# Generated by OpenFakeRAM
VERSION 5.7 ;
BUSBITCHARS "[]" ;
PROPERTYDEFINITIONS
  MACRO width INTEGER ;
  MACRO depth INTEGER ;
  MACRO banks INTEGER ;
END PROPERTYDEFINITIONS
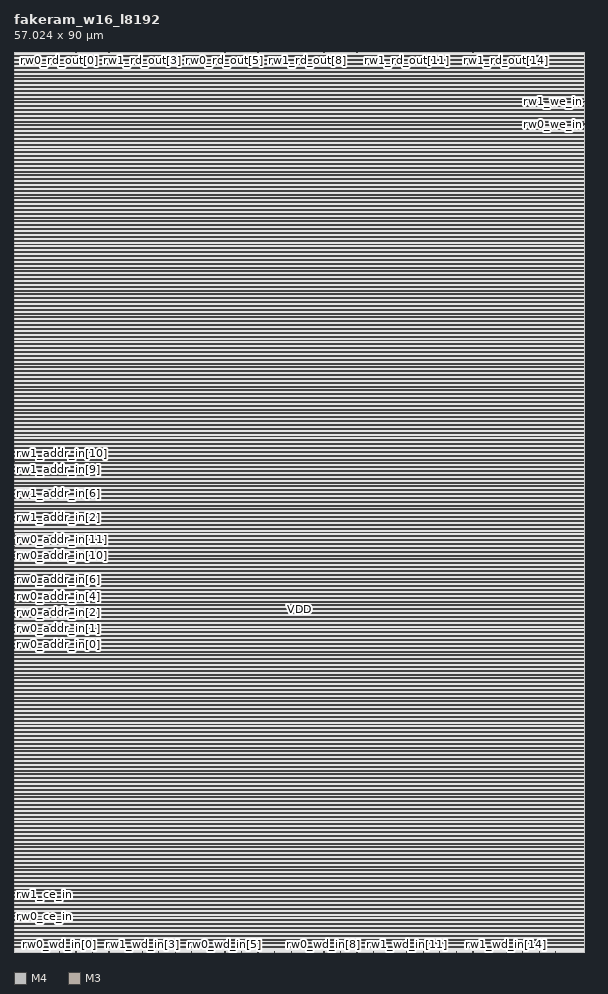
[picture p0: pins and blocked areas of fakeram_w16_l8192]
MACRO fakeram_w16_l8192
  PROPERTY width 16 ;
  PROPERTY depth 4096 ;
  PROPERTY banks 1 ;
  FOREIGN fakeram_w16_l8192 0 0 ;
  SYMMETRY X Y R90 ;
  SIZE 57.024 BY 90.000 ;
  CLASS BLOCK ;
  PIN rw0_clk
    DIRECTION INPUT ;
    USE SIGNAL ;
    SHAPE ABUTMENT ;
    PORT
      LAYER M4 ;
      RECT 0.000 2.724 0.048 2.748 ;
    END
  END rw0_clk
  PIN rw0_ce_in
    DIRECTION INPUT ;
    USE SIGNAL ;
    SHAPE ABUTMENT ;
    PORT
      LAYER M4 ;
      RECT 0.000 3.588 0.048 3.612 ;
    END
  END rw0_ce_in
  PIN rw1_clk
    DIRECTION INPUT ;
    USE SIGNAL ;
    SHAPE ABUTMENT ;
    PORT
      LAYER M4 ;
      RECT 0.000 4.068 0.048 4.092 ;
    END
  END rw1_clk
  PIN rw1_ce_in
    DIRECTION INPUT ;
    USE SIGNAL ;
    SHAPE ABUTMENT ;
    PORT
      LAYER M4 ;
      RECT 0.000 4.932 0.048 4.956 ;
    END
  END rw1_ce_in
  PIN rw0_addr_in[0]
    DIRECTION INPUT ;
    USE SIGNAL ;
    SHAPE ABUTMENT ;
    PORT
      LAYER M4 ;
      RECT 0.000 31.524 0.048 31.548 ;
    END
  END rw0_addr_in[0]
  PIN rw0_addr_in[1]
    DIRECTION INPUT ;
    USE SIGNAL ;
    SHAPE ABUTMENT ;
    PORT
      LAYER M4 ;
      RECT 0.000 32.340 0.048 32.364 ;
    END
  END rw0_addr_in[1]
  PIN rw0_addr_in[2]
    DIRECTION INPUT ;
    USE SIGNAL ;
    SHAPE ABUTMENT ;
    PORT
      LAYER M4 ;
      RECT 0.000 33.156 0.048 33.180 ;
    END
  END rw0_addr_in[2]
  PIN rw0_addr_in[3]
    DIRECTION INPUT ;
    USE SIGNAL ;
    SHAPE ABUTMENT ;
    PORT
      LAYER M4 ;
      RECT 0.000 33.972 0.048 33.996 ;
    END
  END rw0_addr_in[3]
  PIN rw0_addr_in[4]
    DIRECTION INPUT ;
    USE SIGNAL ;
    SHAPE ABUTMENT ;
    PORT
      LAYER M4 ;
      RECT 0.000 34.788 0.048 34.812 ;
    END
  END rw0_addr_in[4]
  PIN rw0_addr_in[5]
    DIRECTION INPUT ;
    USE SIGNAL ;
    SHAPE ABUTMENT ;
    PORT
      LAYER M4 ;
      RECT 0.000 35.604 0.048 35.628 ;
    END
  END rw0_addr_in[5]
  PIN rw0_addr_in[6]
    DIRECTION INPUT ;
    USE SIGNAL ;
    SHAPE ABUTMENT ;
    PORT
      LAYER M4 ;
      RECT 0.000 36.420 0.048 36.444 ;
    END
  END rw0_addr_in[6]
  PIN rw0_addr_in[7]
    DIRECTION INPUT ;
    USE SIGNAL ;
    SHAPE ABUTMENT ;
    PORT
      LAYER M4 ;
      RECT 0.000 37.236 0.048 37.260 ;
    END
  END rw0_addr_in[7]
  PIN rw0_addr_in[8]
    DIRECTION INPUT ;
    USE SIGNAL ;
    SHAPE ABUTMENT ;
    PORT
      LAYER M4 ;
      RECT 0.000 38.052 0.048 38.076 ;
    END
  END rw0_addr_in[8]
  PIN rw0_addr_in[9]
    DIRECTION INPUT ;
    USE SIGNAL ;
    SHAPE ABUTMENT ;
    PORT
      LAYER M4 ;
      RECT 0.000 38.868 0.048 38.892 ;
    END
  END rw0_addr_in[9]
  PIN rw0_addr_in[10]
    DIRECTION INPUT ;
    USE SIGNAL ;
    SHAPE ABUTMENT ;
    PORT
      LAYER M4 ;
      RECT 0.000 39.684 0.048 39.708 ;
    END
  END rw0_addr_in[10]
  PIN rw0_addr_in[11]
    DIRECTION INPUT ;
    USE SIGNAL ;
    SHAPE ABUTMENT ;
    PORT
      LAYER M4 ;
      RECT 0.000 40.500 0.048 40.524 ;
    END
  END rw0_addr_in[11]
  PIN rw1_addr_in[0]
    DIRECTION INPUT ;
    USE SIGNAL ;
    SHAPE ABUTMENT ;
    PORT
      LAYER M4 ;
      RECT 0.000 40.980 0.048 41.004 ;
    END
  END rw1_addr_in[0]
  PIN rw1_addr_in[1]
    DIRECTION INPUT ;
    USE SIGNAL ;
    SHAPE ABUTMENT ;
    PORT
      LAYER M4 ;
      RECT 0.000 41.796 0.048 41.820 ;
    END
  END rw1_addr_in[1]
  PIN rw1_addr_in[2]
    DIRECTION INPUT ;
    USE SIGNAL ;
    SHAPE ABUTMENT ;
    PORT
      LAYER M4 ;
      RECT 0.000 42.612 0.048 42.636 ;
    END
  END rw1_addr_in[2]
  PIN rw1_addr_in[3]
    DIRECTION INPUT ;
    USE SIGNAL ;
    SHAPE ABUTMENT ;
    PORT
      LAYER M4 ;
      RECT 0.000 43.428 0.048 43.452 ;
    END
  END rw1_addr_in[3]
  PIN rw1_addr_in[4]
    DIRECTION INPUT ;
    USE SIGNAL ;
    SHAPE ABUTMENT ;
    PORT
      LAYER M4 ;
      RECT 0.000 44.244 0.048 44.268 ;
    END
  END rw1_addr_in[4]
  PIN rw1_addr_in[5]
    DIRECTION INPUT ;
    USE SIGNAL ;
    SHAPE ABUTMENT ;
    PORT
      LAYER M4 ;
      RECT 0.000 45.060 0.048 45.084 ;
    END
  END rw1_addr_in[5]
  PIN rw1_addr_in[6]
    DIRECTION INPUT ;
    USE SIGNAL ;
    SHAPE ABUTMENT ;
    PORT
      LAYER M4 ;
      RECT 0.000 45.828 0.048 45.852 ;
    END
  END rw1_addr_in[6]
  PIN rw1_addr_in[7]
    DIRECTION INPUT ;
    USE SIGNAL ;
    SHAPE ABUTMENT ;
    PORT
      LAYER M4 ;
      RECT 0.000 46.644 0.048 46.668 ;
    END
  END rw1_addr_in[7]
  PIN rw1_addr_in[8]
    DIRECTION INPUT ;
    USE SIGNAL ;
    SHAPE ABUTMENT ;
    PORT
      LAYER M4 ;
      RECT 0.000 47.460 0.048 47.484 ;
    END
  END rw1_addr_in[8]
  PIN rw1_addr_in[9]
    DIRECTION INPUT ;
    USE SIGNAL ;
    SHAPE ABUTMENT ;
    PORT
      LAYER M4 ;
      RECT 0.000 48.276 0.048 48.300 ;
    END
  END rw1_addr_in[9]
  PIN rw1_addr_in[10]
    DIRECTION INPUT ;
    USE SIGNAL ;
    SHAPE ABUTMENT ;
    PORT
      LAYER M4 ;
      RECT 0.000 49.092 0.048 49.116 ;
    END
  END rw1_addr_in[10]
  PIN rw1_addr_in[11]
    DIRECTION INPUT ;
    USE SIGNAL ;
    SHAPE ABUTMENT ;
    PORT
      LAYER M4 ;
      RECT 0.000 49.908 0.048 49.932 ;
    END
  END rw1_addr_in[11]
  PIN rw1_rd_out[0]
    DIRECTION OUTPUT ;
    USE SIGNAL ;
    SHAPE ABUTMENT ;
    PORT
      LAYER M3 ;
      RECT 2.871 89.964 2.889 90.000 ;
    END
  END rw1_rd_out[0]
  PIN rw0_rd_out[0]
    DIRECTION OUTPUT ;
    USE SIGNAL ;
    SHAPE ABUTMENT ;
    PORT
      LAYER M3 ;
      RECT 4.527 89.964 4.545 90.000 ;
    END
  END rw0_rd_out[0]
  PIN rw1_rd_out[1]
    DIRECTION OUTPUT ;
    USE SIGNAL ;
    SHAPE ABUTMENT ;
    PORT
      LAYER M3 ;
      RECT 6.183 89.964 6.201 90.000 ;
    END
  END rw1_rd_out[1]
  PIN rw0_rd_out[1]
    DIRECTION OUTPUT ;
    USE SIGNAL ;
    SHAPE ABUTMENT ;
    PORT
      LAYER M3 ;
      RECT 7.839 89.964 7.857 90.000 ;
    END
  END rw0_rd_out[1]
  PIN rw1_rd_out[2]
    DIRECTION OUTPUT ;
    USE SIGNAL ;
    SHAPE ABUTMENT ;
    PORT
      LAYER M3 ;
      RECT 9.495 89.964 9.513 90.000 ;
    END
  END rw1_rd_out[2]
  PIN rw0_rd_out[2]
    DIRECTION OUTPUT ;
    USE SIGNAL ;
    SHAPE ABUTMENT ;
    PORT
      LAYER M3 ;
      RECT 11.151 89.964 11.169 90.000 ;
    END
  END rw0_rd_out[2]
  PIN rw1_rd_out[3]
    DIRECTION OUTPUT ;
    USE SIGNAL ;
    SHAPE ABUTMENT ;
    PORT
      LAYER M3 ;
      RECT 12.807 89.964 12.825 90.000 ;
    END
  END rw1_rd_out[3]
  PIN rw0_rd_out[3]
    DIRECTION OUTPUT ;
    USE SIGNAL ;
    SHAPE ABUTMENT ;
    PORT
      LAYER M3 ;
      RECT 14.463 89.964 14.481 90.000 ;
    END
  END rw0_rd_out[3]
  PIN rw1_rd_out[4]
    DIRECTION OUTPUT ;
    USE SIGNAL ;
    SHAPE ABUTMENT ;
    PORT
      LAYER M3 ;
      RECT 16.119 89.964 16.137 90.000 ;
    END
  END rw1_rd_out[4]
  PIN rw0_rd_out[4]
    DIRECTION OUTPUT ;
    USE SIGNAL ;
    SHAPE ABUTMENT ;
    PORT
      LAYER M3 ;
      RECT 17.775 89.964 17.793 90.000 ;
    END
  END rw0_rd_out[4]
  PIN rw1_rd_out[5]
    DIRECTION OUTPUT ;
    USE SIGNAL ;
    SHAPE ABUTMENT ;
    PORT
      LAYER M3 ;
      RECT 19.431 89.964 19.449 90.000 ;
    END
  END rw1_rd_out[5]
  PIN rw0_rd_out[5]
    DIRECTION OUTPUT ;
    USE SIGNAL ;
    SHAPE ABUTMENT ;
    PORT
      LAYER M3 ;
      RECT 21.087 89.964 21.105 90.000 ;
    END
  END rw0_rd_out[5]
  PIN rw1_rd_out[6]
    DIRECTION OUTPUT ;
    USE SIGNAL ;
    SHAPE ABUTMENT ;
    PORT
      LAYER M3 ;
      RECT 22.743 89.964 22.761 90.000 ;
    END
  END rw1_rd_out[6]
  PIN rw0_rd_out[6]
    DIRECTION OUTPUT ;
    USE SIGNAL ;
    SHAPE ABUTMENT ;
    PORT
      LAYER M3 ;
      RECT 24.399 89.964 24.417 90.000 ;
    END
  END rw0_rd_out[6]
  PIN rw1_rd_out[7]
    DIRECTION OUTPUT ;
    USE SIGNAL ;
    SHAPE ABUTMENT ;
    PORT
      LAYER M3 ;
      RECT 26.055 89.964 26.073 90.000 ;
    END
  END rw1_rd_out[7]
  PIN rw0_rd_out[7]
    DIRECTION OUTPUT ;
    USE SIGNAL ;
    SHAPE ABUTMENT ;
    PORT
      LAYER M3 ;
      RECT 27.711 89.964 27.729 90.000 ;
    END
  END rw0_rd_out[7]
  PIN rw1_rd_out[8]
    DIRECTION OUTPUT ;
    USE SIGNAL ;
    SHAPE ABUTMENT ;
    PORT
      LAYER M3 ;
      RECT 29.331 89.964 29.349 90.000 ;
    END
  END rw1_rd_out[8]
  PIN rw0_rd_out[8]
    DIRECTION OUTPUT ;
    USE SIGNAL ;
    SHAPE ABUTMENT ;
    PORT
      LAYER M3 ;
      RECT 30.987 89.964 31.005 90.000 ;
    END
  END rw0_rd_out[8]
  PIN rw1_rd_out[9]
    DIRECTION OUTPUT ;
    USE SIGNAL ;
    SHAPE ABUTMENT ;
    PORT
      LAYER M3 ;
      RECT 32.643 89.964 32.661 90.000 ;
    END
  END rw1_rd_out[9]
  PIN rw0_rd_out[9]
    DIRECTION OUTPUT ;
    USE SIGNAL ;
    SHAPE ABUTMENT ;
    PORT
      LAYER M3 ;
      RECT 34.299 89.964 34.317 90.000 ;
    END
  END rw0_rd_out[9]
  PIN rw1_rd_out[10]
    DIRECTION OUTPUT ;
    USE SIGNAL ;
    SHAPE ABUTMENT ;
    PORT
      LAYER M3 ;
      RECT 35.955 89.964 35.973 90.000 ;
    END
  END rw1_rd_out[10]
  PIN rw0_rd_out[10]
    DIRECTION OUTPUT ;
    USE SIGNAL ;
    SHAPE ABUTMENT ;
    PORT
      LAYER M3 ;
      RECT 37.611 89.964 37.629 90.000 ;
    END
  END rw0_rd_out[10]
  PIN rw1_rd_out[11]
    DIRECTION OUTPUT ;
    USE SIGNAL ;
    SHAPE ABUTMENT ;
    PORT
      LAYER M3 ;
      RECT 39.267 89.964 39.285 90.000 ;
    END
  END rw1_rd_out[11]
  PIN rw0_rd_out[11]
    DIRECTION OUTPUT ;
    USE SIGNAL ;
    SHAPE ABUTMENT ;
    PORT
      LAYER M3 ;
      RECT 40.923 89.964 40.941 90.000 ;
    END
  END rw0_rd_out[11]
  PIN rw1_rd_out[12]
    DIRECTION OUTPUT ;
    USE SIGNAL ;
    SHAPE ABUTMENT ;
    PORT
      LAYER M3 ;
      RECT 42.579 89.964 42.597 90.000 ;
    END
  END rw1_rd_out[12]
  PIN rw0_rd_out[12]
    DIRECTION OUTPUT ;
    USE SIGNAL ;
    SHAPE ABUTMENT ;
    PORT
      LAYER M3 ;
      RECT 44.235 89.964 44.253 90.000 ;
    END
  END rw0_rd_out[12]
  PIN rw1_rd_out[13]
    DIRECTION OUTPUT ;
    USE SIGNAL ;
    SHAPE ABUTMENT ;
    PORT
      LAYER M3 ;
      RECT 45.891 89.964 45.909 90.000 ;
    END
  END rw1_rd_out[13]
  PIN rw0_rd_out[13]
    DIRECTION OUTPUT ;
    USE SIGNAL ;
    SHAPE ABUTMENT ;
    PORT
      LAYER M3 ;
      RECT 47.547 89.964 47.565 90.000 ;
    END
  END rw0_rd_out[13]
  PIN rw1_rd_out[14]
    DIRECTION OUTPUT ;
    USE SIGNAL ;
    SHAPE ABUTMENT ;
    PORT
      LAYER M3 ;
      RECT 49.203 89.964 49.221 90.000 ;
    END
  END rw1_rd_out[14]
  PIN rw0_rd_out[14]
    DIRECTION OUTPUT ;
    USE SIGNAL ;
    SHAPE ABUTMENT ;
    PORT
      LAYER M3 ;
      RECT 50.859 89.964 50.877 90.000 ;
    END
  END rw0_rd_out[14]
  PIN rw1_rd_out[15]
    DIRECTION OUTPUT ;
    USE SIGNAL ;
    SHAPE ABUTMENT ;
    PORT
      LAYER M3 ;
      RECT 52.515 89.964 52.533 90.000 ;
    END
  END rw1_rd_out[15]
  PIN rw0_rd_out[15]
    DIRECTION OUTPUT ;
    USE SIGNAL ;
    SHAPE ABUTMENT ;
    PORT
      LAYER M3 ;
      RECT 54.171 89.964 54.189 90.000 ;
    END
  END rw0_rd_out[15]
  PIN rw0_we_in
    DIRECTION INPUT ;
    USE SIGNAL ;
    SHAPE ABUTMENT ;
    PORT
      LAYER M4 ;
      RECT 56.976 82.788 57.024 82.812 ;
    END
  END rw0_we_in
  PIN rw1_we_in
    DIRECTION INPUT ;
    USE SIGNAL ;
    SHAPE ABUTMENT ;
    PORT
      LAYER M4 ;
      RECT 56.976 85.044 57.024 85.068 ;
    END
  END rw1_we_in
  PIN rw1_wd_in[0]
    DIRECTION INPUT ;
    USE SIGNAL ;
    SHAPE ABUTMENT ;
    PORT
      LAYER M3 ;
      RECT 2.871 0.000 2.889 0.036 ;
    END
  END rw1_wd_in[0]
  PIN rw0_wd_in[0]
    DIRECTION INPUT ;
    USE SIGNAL ;
    SHAPE ABUTMENT ;
    PORT
      LAYER M3 ;
      RECT 4.527 0.000 4.545 0.036 ;
    END
  END rw0_wd_in[0]
  PIN rw1_wd_in[1]
    DIRECTION INPUT ;
    USE SIGNAL ;
    SHAPE ABUTMENT ;
    PORT
      LAYER M3 ;
      RECT 6.183 0.000 6.201 0.036 ;
    END
  END rw1_wd_in[1]
  PIN rw0_wd_in[1]
    DIRECTION INPUT ;
    USE SIGNAL ;
    SHAPE ABUTMENT ;
    PORT
      LAYER M3 ;
      RECT 7.839 0.000 7.857 0.036 ;
    END
  END rw0_wd_in[1]
  PIN rw1_wd_in[2]
    DIRECTION INPUT ;
    USE SIGNAL ;
    SHAPE ABUTMENT ;
    PORT
      LAYER M3 ;
      RECT 9.495 0.000 9.513 0.036 ;
    END
  END rw1_wd_in[2]
  PIN rw0_wd_in[2]
    DIRECTION INPUT ;
    USE SIGNAL ;
    SHAPE ABUTMENT ;
    PORT
      LAYER M3 ;
      RECT 11.151 0.000 11.169 0.036 ;
    END
  END rw0_wd_in[2]
  PIN rw1_wd_in[3]
    DIRECTION INPUT ;
    USE SIGNAL ;
    SHAPE ABUTMENT ;
    PORT
      LAYER M3 ;
      RECT 12.807 0.000 12.825 0.036 ;
    END
  END rw1_wd_in[3]
  PIN rw0_wd_in[3]
    DIRECTION INPUT ;
    USE SIGNAL ;
    SHAPE ABUTMENT ;
    PORT
      LAYER M3 ;
      RECT 14.463 0.000 14.481 0.036 ;
    END
  END rw0_wd_in[3]
  PIN rw1_wd_in[4]
    DIRECTION INPUT ;
    USE SIGNAL ;
    SHAPE ABUTMENT ;
    PORT
      LAYER M3 ;
      RECT 16.119 0.000 16.137 0.036 ;
    END
  END rw1_wd_in[4]
  PIN rw0_wd_in[4]
    DIRECTION INPUT ;
    USE SIGNAL ;
    SHAPE ABUTMENT ;
    PORT
      LAYER M3 ;
      RECT 17.775 0.000 17.793 0.036 ;
    END
  END rw0_wd_in[4]
  PIN rw1_wd_in[5]
    DIRECTION INPUT ;
    USE SIGNAL ;
    SHAPE ABUTMENT ;
    PORT
      LAYER M3 ;
      RECT 19.431 0.000 19.449 0.036 ;
    END
  END rw1_wd_in[5]
  PIN rw0_wd_in[5]
    DIRECTION INPUT ;
    USE SIGNAL ;
    SHAPE ABUTMENT ;
    PORT
      LAYER M3 ;
      RECT 21.087 0.000 21.105 0.036 ;
    END
  END rw0_wd_in[5]
  PIN rw1_wd_in[6]
    DIRECTION INPUT ;
    USE SIGNAL ;
    SHAPE ABUTMENT ;
    PORT
      LAYER M3 ;
      RECT 22.743 0.000 22.761 0.036 ;
    END
  END rw1_wd_in[6]
  PIN rw0_wd_in[6]
    DIRECTION INPUT ;
    USE SIGNAL ;
    SHAPE ABUTMENT ;
    PORT
      LAYER M3 ;
      RECT 24.399 0.000 24.417 0.036 ;
    END
  END rw0_wd_in[6]
  PIN rw1_wd_in[7]
    DIRECTION INPUT ;
    USE SIGNAL ;
    SHAPE ABUTMENT ;
    PORT
      LAYER M3 ;
      RECT 26.055 0.000 26.073 0.036 ;
    END
  END rw1_wd_in[7]
  PIN rw0_wd_in[7]
    DIRECTION INPUT ;
    USE SIGNAL ;
    SHAPE ABUTMENT ;
    PORT
      LAYER M3 ;
      RECT 27.711 0.000 27.729 0.036 ;
    END
  END rw0_wd_in[7]
  PIN rw1_wd_in[8]
    DIRECTION INPUT ;
    USE SIGNAL ;
    SHAPE ABUTMENT ;
    PORT
      LAYER M3 ;
      RECT 29.331 0.000 29.349 0.036 ;
    END
  END rw1_wd_in[8]
  PIN rw0_wd_in[8]
    DIRECTION INPUT ;
    USE SIGNAL ;
    SHAPE ABUTMENT ;
    PORT
      LAYER M3 ;
      RECT 30.987 0.000 31.005 0.036 ;
    END
  END rw0_wd_in[8]
  PIN rw1_wd_in[9]
    DIRECTION INPUT ;
    USE SIGNAL ;
    SHAPE ABUTMENT ;
    PORT
      LAYER M3 ;
      RECT 32.643 0.000 32.661 0.036 ;
    END
  END rw1_wd_in[9]
  PIN rw0_wd_in[9]
    DIRECTION INPUT ;
    USE SIGNAL ;
    SHAPE ABUTMENT ;
    PORT
      LAYER M3 ;
      RECT 34.299 0.000 34.317 0.036 ;
    END
  END rw0_wd_in[9]
  PIN rw1_wd_in[10]
    DIRECTION INPUT ;
    USE SIGNAL ;
    SHAPE ABUTMENT ;
    PORT
      LAYER M3 ;
      RECT 35.955 0.000 35.973 0.036 ;
    END
  END rw1_wd_in[10]
  PIN rw0_wd_in[10]
    DIRECTION INPUT ;
    USE SIGNAL ;
    SHAPE ABUTMENT ;
    PORT
      LAYER M3 ;
      RECT 37.611 0.000 37.629 0.036 ;
    END
  END rw0_wd_in[10]
  PIN rw1_wd_in[11]
    DIRECTION INPUT ;
    USE SIGNAL ;
    SHAPE ABUTMENT ;
    PORT
      LAYER M3 ;
      RECT 39.267 0.000 39.285 0.036 ;
    END
  END rw1_wd_in[11]
  PIN rw0_wd_in[11]
    DIRECTION INPUT ;
    USE SIGNAL ;
    SHAPE ABUTMENT ;
    PORT
      LAYER M3 ;
      RECT 40.923 0.000 40.941 0.036 ;
    END
  END rw0_wd_in[11]
  PIN rw1_wd_in[12]
    DIRECTION INPUT ;
    USE SIGNAL ;
    SHAPE ABUTMENT ;
    PORT
      LAYER M3 ;
      RECT 42.579 0.000 42.597 0.036 ;
    END
  END rw1_wd_in[12]
  PIN rw0_wd_in[12]
    DIRECTION INPUT ;
    USE SIGNAL ;
    SHAPE ABUTMENT ;
    PORT
      LAYER M3 ;
      RECT 44.235 0.000 44.253 0.036 ;
    END
  END rw0_wd_in[12]
  PIN rw1_wd_in[13]
    DIRECTION INPUT ;
    USE SIGNAL ;
    SHAPE ABUTMENT ;
    PORT
      LAYER M3 ;
      RECT 45.891 0.000 45.909 0.036 ;
    END
  END rw1_wd_in[13]
  PIN rw0_wd_in[13]
    DIRECTION INPUT ;
    USE SIGNAL ;
    SHAPE ABUTMENT ;
    PORT
      LAYER M3 ;
      RECT 47.547 0.000 47.565 0.036 ;
    END
  END rw0_wd_in[13]
  PIN rw1_wd_in[14]
    DIRECTION INPUT ;
    USE SIGNAL ;
    SHAPE ABUTMENT ;
    PORT
      LAYER M3 ;
      RECT 49.203 0.000 49.221 0.036 ;
    END
  END rw1_wd_in[14]
  PIN rw0_wd_in[14]
    DIRECTION INPUT ;
    USE SIGNAL ;
    SHAPE ABUTMENT ;
    PORT
      LAYER M3 ;
      RECT 50.859 0.000 50.877 0.036 ;
    END
  END rw0_wd_in[14]
  PIN rw1_wd_in[15]
    DIRECTION INPUT ;
    USE SIGNAL ;
    SHAPE ABUTMENT ;
    PORT
      LAYER M3 ;
      RECT 52.515 0.000 52.533 0.036 ;
    END
  END rw1_wd_in[15]
  PIN rw0_wd_in[15]
    DIRECTION INPUT ;
    USE SIGNAL ;
    SHAPE ABUTMENT ;
    PORT
      LAYER M3 ;
      RECT 54.171 0.000 54.189 0.036 ;
    END
  END rw0_wd_in[15]
  PIN VSS
    DIRECTION INOUT ;
    USE GROUND ;
    PORT
      LAYER M4 ;
      RECT 0.096 0.816 56.928 0.912 ;
      RECT 0.096 1.584 56.928 1.680 ;
      RECT 0.096 2.352 56.928 2.448 ;
      RECT 0.096 3.120 56.928 3.216 ;
      RECT 0.096 3.888 56.928 3.984 ;
      RECT 0.096 4.656 56.928 4.752 ;
      RECT 0.096 5.424 56.928 5.520 ;
      RECT 0.096 6.192 56.928 6.288 ;
      RECT 0.096 6.960 56.928 7.056 ;
      RECT 0.096 7.728 56.928 7.824 ;
      RECT 0.096 8.496 56.928 8.592 ;
      RECT 0.096 9.264 56.928 9.360 ;
      RECT 0.096 10.032 56.928 10.128 ;
      RECT 0.096 10.800 56.928 10.896 ;
      RECT 0.096 11.568 56.928 11.664 ;
      RECT 0.096 12.336 56.928 12.432 ;
      RECT 0.096 13.104 56.928 13.200 ;
      RECT 0.096 13.872 56.928 13.968 ;
      RECT 0.096 14.640 56.928 14.736 ;
      RECT 0.096 15.408 56.928 15.504 ;
      RECT 0.096 16.176 56.928 16.272 ;
      RECT 0.096 16.944 56.928 17.040 ;
      RECT 0.096 17.712 56.928 17.808 ;
      RECT 0.096 18.480 56.928 18.576 ;
      RECT 0.096 19.248 56.928 19.344 ;
      RECT 0.096 20.016 56.928 20.112 ;
      RECT 0.096 20.784 56.928 20.880 ;
      RECT 0.096 21.552 56.928 21.648 ;
      RECT 0.096 22.320 56.928 22.416 ;
      RECT 0.096 23.088 56.928 23.184 ;
      RECT 0.096 23.856 56.928 23.952 ;
      RECT 0.096 24.624 56.928 24.720 ;
      RECT 0.096 25.392 56.928 25.488 ;
      RECT 0.096 26.160 56.928 26.256 ;
      RECT 0.096 26.928 56.928 27.024 ;
      RECT 0.096 27.696 56.928 27.792 ;
      RECT 0.096 28.464 56.928 28.560 ;
      RECT 0.096 29.232 56.928 29.328 ;
      RECT 0.096 30.000 56.928 30.096 ;
      RECT 0.096 30.768 56.928 30.864 ;
      RECT 0.096 31.536 56.928 31.632 ;
      RECT 0.096 32.304 56.928 32.400 ;
      RECT 0.096 33.072 56.928 33.168 ;
      RECT 0.096 33.840 56.928 33.936 ;
      RECT 0.096 34.608 56.928 34.704 ;
      RECT 0.096 35.376 56.928 35.472 ;
      RECT 0.096 36.144 56.928 36.240 ;
      RECT 0.096 36.912 56.928 37.008 ;
      RECT 0.096 37.680 56.928 37.776 ;
      RECT 0.096 38.448 56.928 38.544 ;
      RECT 0.096 39.216 56.928 39.312 ;
      RECT 0.096 39.984 56.928 40.080 ;
      RECT 0.096 40.752 56.928 40.848 ;
      RECT 0.096 41.520 56.928 41.616 ;
      RECT 0.096 42.288 56.928 42.384 ;
      RECT 0.096 43.056 56.928 43.152 ;
      RECT 0.096 43.824 56.928 43.920 ;
      RECT 0.096 44.592 56.928 44.688 ;
      RECT 0.096 45.360 56.928 45.456 ;
      RECT 0.096 46.128 56.928 46.224 ;
      RECT 0.096 46.896 56.928 46.992 ;
      RECT 0.096 47.664 56.928 47.760 ;
      RECT 0.096 48.432 56.928 48.528 ;
      RECT 0.096 49.200 56.928 49.296 ;
      RECT 0.096 49.968 56.928 50.064 ;
      RECT 0.096 50.736 56.928 50.832 ;
      RECT 0.096 51.504 56.928 51.600 ;
      RECT 0.096 52.272 56.928 52.368 ;
      RECT 0.096 53.040 56.928 53.136 ;
      RECT 0.096 53.808 56.928 53.904 ;
      RECT 0.096 54.576 56.928 54.672 ;
      RECT 0.096 55.344 56.928 55.440 ;
      RECT 0.096 56.112 56.928 56.208 ;
      RECT 0.096 56.880 56.928 56.976 ;
      RECT 0.096 57.648 56.928 57.744 ;
      RECT 0.096 58.416 56.928 58.512 ;
      RECT 0.096 59.184 56.928 59.280 ;
      RECT 0.096 59.952 56.928 60.048 ;
      RECT 0.096 60.720 56.928 60.816 ;
      RECT 0.096 61.488 56.928 61.584 ;
      RECT 0.096 62.256 56.928 62.352 ;
      RECT 0.096 63.024 56.928 63.120 ;
      RECT 0.096 63.792 56.928 63.888 ;
      RECT 0.096 64.560 56.928 64.656 ;
      RECT 0.096 65.328 56.928 65.424 ;
      RECT 0.096 66.096 56.928 66.192 ;
      RECT 0.096 66.864 56.928 66.960 ;
      RECT 0.096 67.632 56.928 67.728 ;
      RECT 0.096 68.400 56.928 68.496 ;
      RECT 0.096 69.168 56.928 69.264 ;
      RECT 0.096 69.936 56.928 70.032 ;
      RECT 0.096 70.704 56.928 70.800 ;
      RECT 0.096 71.472 56.928 71.568 ;
      RECT 0.096 72.240 56.928 72.336 ;
      RECT 0.096 73.008 56.928 73.104 ;
      RECT 0.096 73.776 56.928 73.872 ;
      RECT 0.096 74.544 56.928 74.640 ;
      RECT 0.096 75.312 56.928 75.408 ;
      RECT 0.096 76.080 56.928 76.176 ;
      RECT 0.096 76.848 56.928 76.944 ;
      RECT 0.096 77.616 56.928 77.712 ;
      RECT 0.096 78.384 56.928 78.480 ;
      RECT 0.096 79.152 56.928 79.248 ;
      RECT 0.096 79.920 56.928 80.016 ;
      RECT 0.096 80.688 56.928 80.784 ;
      RECT 0.096 81.456 56.928 81.552 ;
      RECT 0.096 82.224 56.928 82.320 ;
      RECT 0.096 82.992 56.928 83.088 ;
      RECT 0.096 83.760 56.928 83.856 ;
      RECT 0.096 84.528 56.928 84.624 ;
      RECT 0.096 85.296 56.928 85.392 ;
      RECT 0.096 86.064 56.928 86.160 ;
      RECT 0.096 86.832 56.928 86.928 ;
      RECT 0.096 87.600 56.928 87.696 ;
      RECT 0.096 88.368 56.928 88.464 ;
      RECT 0.096 89.136 56.928 89.232 ;
    END
  END VSS
  PIN VDD
    DIRECTION INOUT ;
    USE POWER ;
    PORT
      LAYER M4 ;
      RECT 0.096 0.432 56.928 0.528 ;
      RECT 0.096 1.200 56.928 1.296 ;
      RECT 0.096 1.968 56.928 2.064 ;
      RECT 0.096 2.736 56.928 2.832 ;
      RECT 0.096 3.504 56.928 3.600 ;
      RECT 0.096 4.272 56.928 4.368 ;
      RECT 0.096 5.040 56.928 5.136 ;
      RECT 0.096 5.808 56.928 5.904 ;
      RECT 0.096 6.576 56.928 6.672 ;
      RECT 0.096 7.344 56.928 7.440 ;
      RECT 0.096 8.112 56.928 8.208 ;
      RECT 0.096 8.880 56.928 8.976 ;
      RECT 0.096 9.648 56.928 9.744 ;
      RECT 0.096 10.416 56.928 10.512 ;
      RECT 0.096 11.184 56.928 11.280 ;
      RECT 0.096 11.952 56.928 12.048 ;
      RECT 0.096 12.720 56.928 12.816 ;
      RECT 0.096 13.488 56.928 13.584 ;
      RECT 0.096 14.256 56.928 14.352 ;
      RECT 0.096 15.024 56.928 15.120 ;
      RECT 0.096 15.792 56.928 15.888 ;
      RECT 0.096 16.560 56.928 16.656 ;
      RECT 0.096 17.328 56.928 17.424 ;
      RECT 0.096 18.096 56.928 18.192 ;
      RECT 0.096 18.864 56.928 18.960 ;
      RECT 0.096 19.632 56.928 19.728 ;
      RECT 0.096 20.400 56.928 20.496 ;
      RECT 0.096 21.168 56.928 21.264 ;
      RECT 0.096 21.936 56.928 22.032 ;
      RECT 0.096 22.704 56.928 22.800 ;
      RECT 0.096 23.472 56.928 23.568 ;
      RECT 0.096 24.240 56.928 24.336 ;
      RECT 0.096 25.008 56.928 25.104 ;
      RECT 0.096 25.776 56.928 25.872 ;
      RECT 0.096 26.544 56.928 26.640 ;
      RECT 0.096 27.312 56.928 27.408 ;
      RECT 0.096 28.080 56.928 28.176 ;
      RECT 0.096 28.848 56.928 28.944 ;
      RECT 0.096 29.616 56.928 29.712 ;
      RECT 0.096 30.384 56.928 30.480 ;
      RECT 0.096 31.152 56.928 31.248 ;
      RECT 0.096 31.920 56.928 32.016 ;
      RECT 0.096 32.688 56.928 32.784 ;
      RECT 0.096 33.456 56.928 33.552 ;
      RECT 0.096 34.224 56.928 34.320 ;
      RECT 0.096 34.992 56.928 35.088 ;
      RECT 0.096 35.760 56.928 35.856 ;
      RECT 0.096 36.528 56.928 36.624 ;
      RECT 0.096 37.296 56.928 37.392 ;
      RECT 0.096 38.064 56.928 38.160 ;
      RECT 0.096 38.832 56.928 38.928 ;
      RECT 0.096 39.600 56.928 39.696 ;
      RECT 0.096 40.368 56.928 40.464 ;
      RECT 0.096 41.136 56.928 41.232 ;
      RECT 0.096 41.904 56.928 42.000 ;
      RECT 0.096 42.672 56.928 42.768 ;
      RECT 0.096 43.440 56.928 43.536 ;
      RECT 0.096 44.208 56.928 44.304 ;
      RECT 0.096 44.976 56.928 45.072 ;
      RECT 0.096 45.744 56.928 45.840 ;
      RECT 0.096 46.512 56.928 46.608 ;
      RECT 0.096 47.280 56.928 47.376 ;
      RECT 0.096 48.048 56.928 48.144 ;
      RECT 0.096 48.816 56.928 48.912 ;
      RECT 0.096 49.584 56.928 49.680 ;
      RECT 0.096 50.352 56.928 50.448 ;
      RECT 0.096 51.120 56.928 51.216 ;
      RECT 0.096 51.888 56.928 51.984 ;
      RECT 0.096 52.656 56.928 52.752 ;
      RECT 0.096 53.424 56.928 53.520 ;
      RECT 0.096 54.192 56.928 54.288 ;
      RECT 0.096 54.960 56.928 55.056 ;
      RECT 0.096 55.728 56.928 55.824 ;
      RECT 0.096 56.496 56.928 56.592 ;
      RECT 0.096 57.264 56.928 57.360 ;
      RECT 0.096 58.032 56.928 58.128 ;
      RECT 0.096 58.800 56.928 58.896 ;
      RECT 0.096 59.568 56.928 59.664 ;
      RECT 0.096 60.336 56.928 60.432 ;
      RECT 0.096 61.104 56.928 61.200 ;
      RECT 0.096 61.872 56.928 61.968 ;
      RECT 0.096 62.640 56.928 62.736 ;
      RECT 0.096 63.408 56.928 63.504 ;
      RECT 0.096 64.176 56.928 64.272 ;
      RECT 0.096 64.944 56.928 65.040 ;
      RECT 0.096 65.712 56.928 65.808 ;
      RECT 0.096 66.480 56.928 66.576 ;
      RECT 0.096 67.248 56.928 67.344 ;
      RECT 0.096 68.016 56.928 68.112 ;
      RECT 0.096 68.784 56.928 68.880 ;
      RECT 0.096 69.552 56.928 69.648 ;
      RECT 0.096 70.320 56.928 70.416 ;
      RECT 0.096 71.088 56.928 71.184 ;
      RECT 0.096 71.856 56.928 71.952 ;
      RECT 0.096 72.624 56.928 72.720 ;
      RECT 0.096 73.392 56.928 73.488 ;
      RECT 0.096 74.160 56.928 74.256 ;
      RECT 0.096 74.928 56.928 75.024 ;
      RECT 0.096 75.696 56.928 75.792 ;
      RECT 0.096 76.464 56.928 76.560 ;
      RECT 0.096 77.232 56.928 77.328 ;
      RECT 0.096 78.000 56.928 78.096 ;
      RECT 0.096 78.768 56.928 78.864 ;
      RECT 0.096 79.536 56.928 79.632 ;
      RECT 0.096 80.304 56.928 80.400 ;
      RECT 0.096 81.072 56.928 81.168 ;
      RECT 0.096 81.840 56.928 81.936 ;
      RECT 0.096 82.608 56.928 82.704 ;
      RECT 0.096 83.376 56.928 83.472 ;
      RECT 0.096 84.144 56.928 84.240 ;
      RECT 0.096 84.912 56.928 85.008 ;
      RECT 0.096 85.680 56.928 85.776 ;
      RECT 0.096 86.448 56.928 86.544 ;
      RECT 0.096 87.216 56.928 87.312 ;
      RECT 0.096 87.984 56.928 88.080 ;
      RECT 0.096 88.752 56.928 88.848 ;
      RECT 0.096 89.520 56.928 89.616 ;
    END
  END VDD
  OBS
    LAYER M1 ;
    RECT 0 0 57.024 90.000 ;
    LAYER M2 ;
    RECT 0 0 57.024 90.000 ;
    LAYER M3 ;
    RECT 0 0 57.024 90.000 ;
    LAYER M4 ;
    RECT 0 0 57.024 90.000 ;
  END
END fakeram_w16_l8192

END LIBRARY
